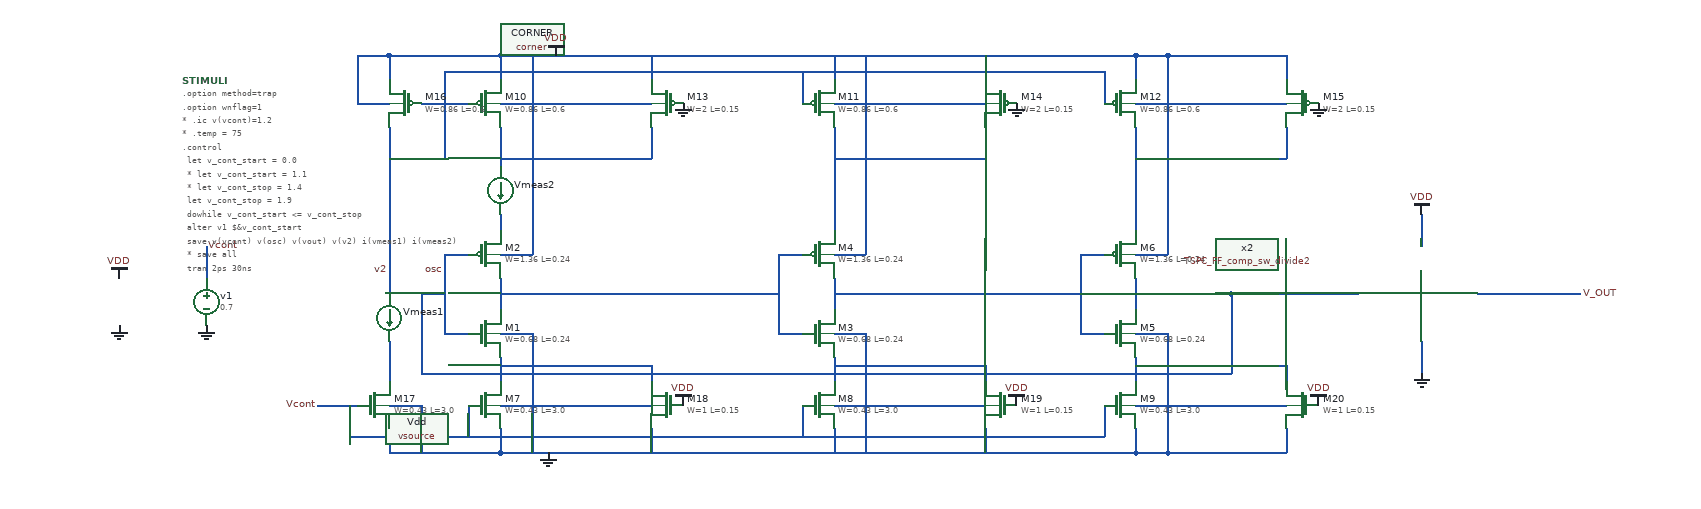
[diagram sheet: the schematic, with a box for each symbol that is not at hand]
v {xschem version=3.4.5 file_version=1.2
}
G {}
K {}
V {}
S {}
E {}
B 2 20 -1720 1940 -940 {flags=graph
y1=-0.059
y2=1.9
ypos1=0
ypos2=2
divy=5
subdivy=1
unity=1
x1=1.8385173e-08
x2=1.8913958e-08
divx=5
subdivx=4
xlabmag=1.0
ylabmag=1.0


dataset=-1
unitx=1
logx=0
logy=0
linewidth_mult=3




color=5
node=osc}
N 200 -640 200 -600 {
lab=Vcont}
N 570 -600 570 -560 {
lab=#net1}
N 500 -630 530 -630 {
lab=osc}
N 500 -630 500 -530 {
lab=osc}
N 500 -530 530 -530 {
lab=osc}
N 990 -600 990 -560 {
lab=#net2}
N 920 -630 950 -630 {
lab=#net1}
N 920 -630 920 -530 {
lab=#net1}
N 920 -530 950 -530 {
lab=#net1}
N 570 -580 920 -580 {
lab=#net1}
N 1370 -600 1370 -560 {
lab=osc}
N 1300 -630 1330 -630 {
lab=#net2}
N 1300 -630 1300 -530 {
lab=#net2}
N 1300 -530 1330 -530 {
lab=#net2}
N 990 -580 1300 -580 {
lab=#net2}
N 570 -410 570 -380 {
lab=GND}
N 570 -380 1370 -380 {
lab=GND}
N 1370 -410 1370 -380 {
lab=GND}
N 990 -410 990 -380 {
lab=GND}
N 1370 -580 1490 -580 {
lab=osc}
N 1490 -580 1490 -480 {
lab=osc}
N 470 -480 1490 -480 {
lab=osc}
N 470 -580 470 -480 {
lab=osc}
N 470 -580 500 -580 {
lab=osc}
N 570 -790 570 -740 {
lab=#net3}
N 570 -880 570 -850 {
lab=VDD}
N 570 -880 1370 -880 {
lab=VDD}
N 1370 -880 1370 -850 {
lab=VDD}
N 990 -880 990 -850 {
lab=VDD}
N 430 -880 430 -850 {
lab=VDD}
N 430 -880 570 -880 {
lab=VDD}
N 500 -820 500 -750 {
lab=v2}
N 430 -750 500 -750 {
lab=v2}
N 430 -410 430 -380 {
lab=GND}
N 430 -380 570 -380 {
lab=GND}
N 340 -440 390 -440 {
lab=Vcont}
N 1370 -500 1370 -470 {
lab=#net4}
N 990 -500 990 -470 {
lab=#net5}
N 570 -500 570 -470 {
lab=#net6}
N 570 -630 610 -630 {
lab=VDD}
N 610 -880 610 -630 {
lab=VDD}
N 570 -530 610 -530 {
lab=GND}
N 610 -530 610 -380 {
lab=GND}
N 570 -440 610 -440 {
lab=GND}
N 990 -530 1030 -530 {
lab=GND}
N 1030 -530 1030 -380 {
lab=GND}
N 990 -440 1030 -440 {
lab=GND}
N 1370 -530 1410 -530 {
lab=GND}
N 1410 -530 1410 -380 {
lab=GND}
N 1370 -380 1410 -380 {
lab=GND}
N 1370 -440 1410 -440 {
lab=GND}
N 470 -820 530 -820 {
lab=v2}
N 570 -820 610 -820 {
lab=VDD}
N 990 -820 1030 -820 {
lab=VDD}
N 990 -630 1030 -630 {
lab=VDD}
N 1030 -880 1030 -630 {
lab=VDD}
N 1370 -820 1410 -820 {
lab=VDD}
N 1370 -880 1410 -880 {
lab=VDD}
N 1410 -880 1410 -630 {
lab=VDD}
N 1370 -630 1410 -630 {
lab=VDD}
N 500 -860 500 -820 {
lab=v2}
N 500 -860 1330 -860 {
lab=v2}
N 1330 -860 1330 -820 {
lab=v2}
N 950 -860 950 -820 {
lab=v2}
N 380 -440 380 -400 {
lab=Vcont}
N 380 -400 1330 -400 {
lab=Vcont}
N 1330 -440 1330 -400 {
lab=Vcont}
N 950 -440 950 -400 {
lab=Vcont}
N 530 -440 530 -400 {
lab=Vcont}
N 390 -820 430 -820 {
lab=VDD}
N 390 -880 390 -820 {
lab=VDD}
N 390 -880 430 -880 {
lab=VDD}
N 430 -440 470 -440 {
lab=GND}
N 470 -440 470 -380 {
lab=GND}
N 430 -520 430 -470 {
lab=#net7}
N 430 -790 430 -580 {
lab=v2}
N 760 -880 760 -850 {
lab=VDD}
N 610 -820 760 -820 {
lab=VDD}
N 760 -790 760 -750 {
lab=#net3}
N 570 -750 760 -750 {
lab=#net3}
N 1180 -880 1180 -850 {
lab=VDD}
N 1030 -820 1180 -820 {
lab=VDD}
N 990 -750 1180 -750 {
lab=#net8}
N 1180 -790 1180 -750 {
lab=#net8}
N 1560 -880 1560 -850 {
lab=VDD}
N 1410 -820 1560 -820 {
lab=VDD}
N 1370 -750 1560 -750 {
lab=#net9}
N 1560 -790 1560 -750 {
lab=#net9}
N 1410 -880 1560 -880 {
lab=VDD}
N 570 -490 760 -490 {
lab=#net6}
N 760 -490 760 -460 {
lab=#net6}
N 610 -440 760 -440 {
lab=GND}
N 760 -410 760 -380 {
lab=GND}
N 990 -490 1180 -490 {
lab=#net5}
N 1180 -490 1180 -460 {
lab=#net5}
N 1030 -440 1180 -440 {
lab=GND}
N 1180 -410 1180 -380 {
lab=GND}
N 1370 -490 1560 -490 {
lab=#net4}
N 1560 -490 1560 -460 {
lab=#net4}
N 1410 -440 1560 -440 {
lab=GND}
N 1560 -410 1560 -380 {
lab=GND}
N 1410 -380 1560 -380 {
lab=GND}
N 1370 -790 1370 -660 {
lab=#net9}
N 990 -790 990 -660 {
lab=#net8}
N 570 -680 570 -660 {
lab=#net10}
N 1730 -680 1730 -640 {
lab=VDD}
N 1730 -520 1730 -480 {
lab=GND}
N 1800 -580 1930 -580 {
lab=V_OUT}
N 1490 -580 1650 -580 {
lab=osc}
C {devices/vsource.sym} 90 -570 0 0 {name=Vdd value=1.8 savecurrent=false
* "pwl()"}
C {devices/gnd.sym} 90 -540 0 0 {name=l3 lab=GND}
C {devices/vdd.sym} 90 -600 0 0 {name=l4 lab=VDD}
C {devices/vsource.sym} 200 -570 0 0 {name=v1 value=0.7 savecurrent=false}
C {devices/gnd.sym} 200 -540 0 0 {name=l5 lab=GND}
C {devices/lab_pin.sym} 200 -640 0 1 {name=p1 sig_type=std_logic lab=Vcont}
C {sky130_fd_pr/corner.sym} 30 -850 0 0 {name=CORNER only_toplevel=false corner=tt}
C {devices/code.sym} 170 -848.75 0 0 {name=STIMULI only_toplevel=false value="

.option method=trap
.option wnflag=1


* .ic v(vcont)=1.2

* .temp = 75

.control

  let v_cont_start = 0.0
  * let v_cont_start = 1.1
  * let v_cont_stop = 1.4
  let v_cont_stop = 1.9  

  dowhile v_cont_start <= v_cont_stop
    alter v1 $&v_cont_start
    save v(vcont) v(osc) v(vout) v(v2) i(vmeas1) i(vmeas2)
    * save all
    tran 2ps 30ns
    remzerovec
    write tb_current_starved_VCO4_7_\{$&v_cont_start\}.raw
    * write tb_current_starved_VCO4_7_.raw
    linearize v(osc)
    let filename = v_cont_start * 100
    wrdata /foss/designs/my_design/projects/pll/vco/xschem_ngspice/tb_current_starved_VCO4_7_\{$&filename\}.txt v(osc)
    set appendwrite

    reset
    let v_cont_start = v_cont_start + 0.1
  end
.endc


"}
C {devices/vdd.sym} 640 -880 0 0 {name=l1 lab=VDD}
C {devices/gnd.sym} 630 -380 0 0 {name=l2 lab=GND}
C {sky130_fd_pr/nfet_01v8.sym} 550 -530 0 0 {name=M1
L=0.24
W=0.68
nf=1 
mult=1
ad="'int((nf+1)/2) * W/nf * 0.29'" 
pd="'2*int((nf+1)/2) * (W/nf + 0.29)'"
as="'int((nf+2)/2) * W/nf * 0.29'" 
ps="'2*int((nf+2)/2) * (W/nf + 0.29)'"
nrd="'0.29 / W'" nrs="'0.29 / W'"
sa=0 sb=0 sd=0
model=nfet_01v8
spiceprefix=X
}
C {sky130_fd_pr/pfet_01v8.sym} 550 -630 0 0 {name=M2
L=0.24
W=1.36
nf=2
mult=1
ad="'int((nf+1)/2) * W/nf * 0.29'" 
pd="'2*int((nf+1)/2) * (W/nf + 0.29)'"
as="'int((nf+2)/2) * W/nf * 0.29'" 
ps="'2*int((nf+2)/2) * (W/nf + 0.29)'"
nrd="'0.29 / W'" nrs="'0.29 / W'"
sa=0 sb=0 sd=0
model=pfet_01v8
spiceprefix=X
}
C {sky130_fd_pr/nfet_01v8.sym} 970 -530 0 0 {name=M3
L=0.24
W=0.68
nf=1 
mult=1
ad="'int((nf+1)/2) * W/nf * 0.29'" 
pd="'2*int((nf+1)/2) * (W/nf + 0.29)'"
as="'int((nf+2)/2) * W/nf * 0.29'" 
ps="'2*int((nf+2)/2) * (W/nf + 0.29)'"
nrd="'0.29 / W'" nrs="'0.29 / W'"
sa=0 sb=0 sd=0
model=nfet_01v8
spiceprefix=X
}
C {sky130_fd_pr/pfet_01v8.sym} 970 -630 0 0 {name=M4
L=0.24
W=1.36
nf=2
mult=1
ad="'int((nf+1)/2) * W/nf * 0.29'" 
pd="'2*int((nf+1)/2) * (W/nf + 0.29)'"
as="'int((nf+2)/2) * W/nf * 0.29'" 
ps="'2*int((nf+2)/2) * (W/nf + 0.29)'"
nrd="'0.29 / W'" nrs="'0.29 / W'"
sa=0 sb=0 sd=0
model=pfet_01v8
spiceprefix=X
}
C {sky130_fd_pr/nfet_01v8.sym} 1350 -530 0 0 {name=M5
L=0.24
W=0.68
nf=1 
mult=1
ad="'int((nf+1)/2) * W/nf * 0.29'" 
pd="'2*int((nf+1)/2) * (W/nf + 0.29)'"
as="'int((nf+2)/2) * W/nf * 0.29'" 
ps="'2*int((nf+2)/2) * (W/nf + 0.29)'"
nrd="'0.29 / W'" nrs="'0.29 / W'"
sa=0 sb=0 sd=0
model=nfet_01v8
spiceprefix=X
}
C {sky130_fd_pr/pfet_01v8.sym} 1350 -630 0 0 {name=M6
L=0.24
W=1.36
nf=2
mult=1
ad="'int((nf+1)/2) * W/nf * 0.29'" 
pd="'2*int((nf+1)/2) * (W/nf + 0.29)'"
as="'int((nf+2)/2) * W/nf * 0.29'" 
ps="'2*int((nf+2)/2) * (W/nf + 0.29)'"
nrd="'0.29 / W'" nrs="'0.29 / W'"
sa=0 sb=0 sd=0
model=pfet_01v8
spiceprefix=X
}
C {sky130_fd_pr/nfet_01v8.sym} 550 -440 0 0 {name=M7
L=3.0
W=0.43
nf=1 
mult=1
ad="'int((nf+1)/2) * W/nf * 0.29'" 
pd="'2*int((nf+1)/2) * (W/nf + 0.29)'"
as="'int((nf+2)/2) * W/nf * 0.29'" 
ps="'2*int((nf+2)/2) * (W/nf + 0.29)'"
nrd="'0.29 / W'" nrs="'0.29 / W'"
sa=0 sb=0 sd=0
model=nfet_01v8
spiceprefix=X
}
C {sky130_fd_pr/nfet_01v8.sym} 970 -440 0 0 {name=M8
L=3.0
W=0.43
nf=1 
mult=1
ad="'int((nf+1)/2) * W/nf * 0.29'" 
pd="'2*int((nf+1)/2) * (W/nf + 0.29)'"
as="'int((nf+2)/2) * W/nf * 0.29'" 
ps="'2*int((nf+2)/2) * (W/nf + 0.29)'"
nrd="'0.29 / W'" nrs="'0.29 / W'"
sa=0 sb=0 sd=0
model=nfet_01v8
spiceprefix=X
}
C {sky130_fd_pr/nfet_01v8.sym} 1350 -440 0 0 {name=M9
L=3.0
W=0.43
nf=1 
mult=1
ad="'int((nf+1)/2) * W/nf * 0.29'" 
pd="'2*int((nf+1)/2) * (W/nf + 0.29)'"
as="'int((nf+2)/2) * W/nf * 0.29'" 
ps="'2*int((nf+2)/2) * (W/nf + 0.29)'"
nrd="'0.29 / W'" nrs="'0.29 / W'"
sa=0 sb=0 sd=0
model=nfet_01v8
spiceprefix=X
}
C {sky130_fd_pr/pfet_01v8.sym} 550 -820 0 0 {name=M10
L=0.6
W=0.86
nf=1
mult=1
ad="'int((nf+1)/2) * W/nf * 0.29'" 
pd="'2*int((nf+1)/2) * (W/nf + 0.29)'"
as="'int((nf+2)/2) * W/nf * 0.29'" 
ps="'2*int((nf+2)/2) * (W/nf + 0.29)'"
nrd="'0.29 / W'" nrs="'0.29 / W'"
sa=0 sb=0 sd=0
model=pfet_01v8
spiceprefix=X
}
C {sky130_fd_pr/pfet_01v8.sym} 970 -820 0 0 {name=M11
L=0.6
W=0.86
nf=1
mult=1
ad="'int((nf+1)/2) * W/nf * 0.29'" 
pd="'2*int((nf+1)/2) * (W/nf + 0.29)'"
as="'int((nf+2)/2) * W/nf * 0.29'" 
ps="'2*int((nf+2)/2) * (W/nf + 0.29)'"
nrd="'0.29 / W'" nrs="'0.29 / W'"
sa=0 sb=0 sd=0
model=pfet_01v8
spiceprefix=X
}
C {sky130_fd_pr/pfet_01v8.sym} 1350 -820 0 0 {name=M12
L=0.6
W=0.86
nf=1
mult=1
ad="'int((nf+1)/2) * W/nf * 0.29'" 
pd="'2*int((nf+1)/2) * (W/nf + 0.29)'"
as="'int((nf+2)/2) * W/nf * 0.29'" 
ps="'2*int((nf+2)/2) * (W/nf + 0.29)'"
nrd="'0.29 / W'" nrs="'0.29 / W'"
sa=0 sb=0 sd=0
model=pfet_01v8
spiceprefix=X
}
C {sky130_fd_pr/pfet_01v8.sym} 450 -820 0 1 {name=M16
L=0.6
W=0.86
nf=1
mult=1
ad="'int((nf+1)/2) * W/nf * 0.29'" 
pd="'2*int((nf+1)/2) * (W/nf + 0.29)'"
as="'int((nf+2)/2) * W/nf * 0.29'" 
ps="'2*int((nf+2)/2) * (W/nf + 0.29)'"
nrd="'0.29 / W'" nrs="'0.29 / W'"
sa=0 sb=0 sd=0
model=pfet_01v8
spiceprefix=X
}
C {sky130_fd_pr/nfet_01v8.sym} 410 -440 0 0 {name=M17
L=3.0
W=0.43
nf=1 
mult=1
ad="'int((nf+1)/2) * W/nf * 0.29'" 
pd="'2*int((nf+1)/2) * (W/nf + 0.29)'"
as="'int((nf+2)/2) * W/nf * 0.29'" 
ps="'2*int((nf+2)/2) * (W/nf + 0.29)'"
nrd="'0.29 / W'" nrs="'0.29 / W'"
sa=0 sb=0 sd=0
model=nfet_01v8
spiceprefix=X
}
C {devices/lab_pin.sym} 340 -440 0 0 {name=p2 sig_type=std_logic lab=Vcont}
C {devices/lab_pin.sym} 500 -610 0 0 {name=p3 sig_type=std_logic lab=osc}
C {devices/lab_pin.sym} 430 -610 0 0 {name=p4 sig_type=std_logic lab=v2}
C {devices/ammeter.sym} 430 -550 0 0 {name=Vmeas1 savecurrent=true spice_ignore=0}
C {sky130_fd_pr/pfet_01v8.sym} 780 -820 0 1 {name=M13
L=0.15
W=2
nf=2
mult=1
ad="'int((nf+1)/2) * W/nf * 0.29'" 
pd="'2*int((nf+1)/2) * (W/nf + 0.29)'"
as="'int((nf+2)/2) * W/nf * 0.29'" 
ps="'2*int((nf+2)/2) * (W/nf + 0.29)'"
nrd="'0.29 / W'" nrs="'0.29 / W'"
sa=0 sb=0 sd=0
model=pfet_01v8
spiceprefix=X
}
C {devices/gnd.sym} 800 -820 0 0 {name=l6 lab=GND}
C {sky130_fd_pr/pfet_01v8.sym} 1200 -820 0 1 {name=M14
L=0.15
W=2
nf=2
mult=1
ad="'int((nf+1)/2) * W/nf * 0.29'" 
pd="'2*int((nf+1)/2) * (W/nf + 0.29)'"
as="'int((nf+2)/2) * W/nf * 0.29'" 
ps="'2*int((nf+2)/2) * (W/nf + 0.29)'"
nrd="'0.29 / W'" nrs="'0.29 / W'"
sa=0 sb=0 sd=0
model=pfet_01v8
spiceprefix=X
}
C {devices/gnd.sym} 1220 -820 0 0 {name=l7 lab=GND}
C {sky130_fd_pr/pfet_01v8.sym} 1580 -820 0 1 {name=M15
L=0.15
W=2
nf=2
mult=1
ad="'int((nf+1)/2) * W/nf * 0.29'" 
pd="'2*int((nf+1)/2) * (W/nf + 0.29)'"
as="'int((nf+2)/2) * W/nf * 0.29'" 
ps="'2*int((nf+2)/2) * (W/nf + 0.29)'"
nrd="'0.29 / W'" nrs="'0.29 / W'"
sa=0 sb=0 sd=0
model=pfet_01v8
spiceprefix=X
}
C {devices/gnd.sym} 1600 -820 0 0 {name=l8 lab=GND}
C {sky130_fd_pr/nfet_01v8.sym} 780 -440 0 1 {name=M18
L=0.15
W=1
nf=1 
mult=1
ad="'int((nf+1)/2) * W/nf * 0.29'" 
pd="'2*int((nf+1)/2) * (W/nf + 0.29)'"
as="'int((nf+2)/2) * W/nf * 0.29'" 
ps="'2*int((nf+2)/2) * (W/nf + 0.29)'"
nrd="'0.29 / W'" nrs="'0.29 / W'"
sa=0 sb=0 sd=0
model=nfet_01v8
spiceprefix=X
}
C {devices/vdd.sym} 800 -440 0 0 {name=l9 lab=VDD}
C {sky130_fd_pr/nfet_01v8.sym} 1200 -440 0 1 {name=M19
L=0.15
W=1
nf=1 
mult=1
ad="'int((nf+1)/2) * W/nf * 0.29'" 
pd="'2*int((nf+1)/2) * (W/nf + 0.29)'"
as="'int((nf+2)/2) * W/nf * 0.29'" 
ps="'2*int((nf+2)/2) * (W/nf + 0.29)'"
nrd="'0.29 / W'" nrs="'0.29 / W'"
sa=0 sb=0 sd=0
model=nfet_01v8
spiceprefix=X
}
C {devices/vdd.sym} 1220 -440 0 0 {name=l10 lab=VDD}
C {sky130_fd_pr/nfet_01v8.sym} 1580 -440 0 1 {name=M20
L=0.15
W=1
nf=1 
mult=1
ad="'int((nf+1)/2) * W/nf * 0.29'" 
pd="'2*int((nf+1)/2) * (W/nf + 0.29)'"
as="'int((nf+2)/2) * W/nf * 0.29'" 
ps="'2*int((nf+2)/2) * (W/nf + 0.29)'"
nrd="'0.29 / W'" nrs="'0.29 / W'"
sa=0 sb=0 sd=0
model=nfet_01v8
spiceprefix=X
}
C {devices/vdd.sym} 1600 -440 0 0 {name=l11 lab=VDD}
C {devices/ammeter.sym} 570 -710 0 0 {name=Vmeas2 savecurrent=true spice_ignore=0}
C {devices/vdd.sym} 1730 -680 0 0 {name=l12 lab=VDD}
C {devices/gnd.sym} 1730 -480 0 0 {name=l13 lab=GND}
C {devices/lab_pin.sym} 1930 -580 0 1 {name=p5 sig_type=std_logic lab=V_OUT}
C {/foss/designs/my_design/projects/pll/divider/xschem_ngspice/TSPC_FF_comp_sw_divide2.sym} 1730 -580 0 0 {name=x2}
